One B-rep face of a CAD part: STEP entity #511.
In plain terms, the planar face has unit normal (1, 0, 0).
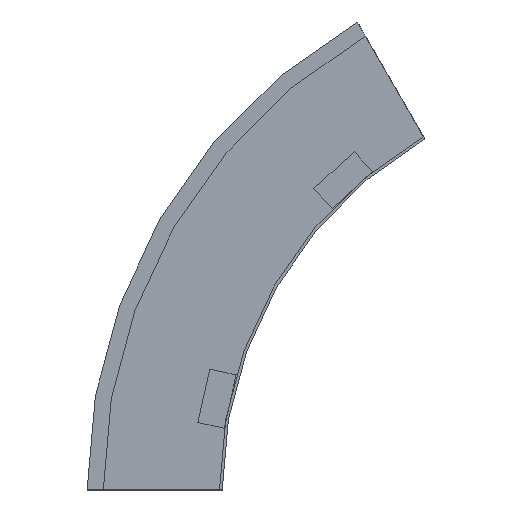
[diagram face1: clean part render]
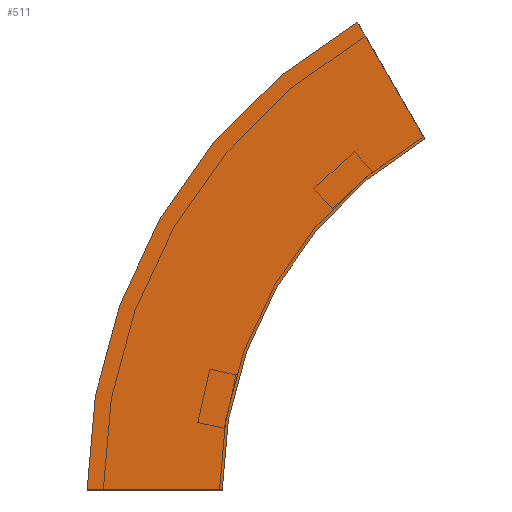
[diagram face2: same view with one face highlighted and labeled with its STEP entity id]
Its self-contained STEP definition (entity closure, numbers rounded to 3 decimals):
#20 = CARTESIAN_POINT ( 'NONE',  ( 0., -300., 0. ) ) ;
#27 = DIRECTION ( 'NONE',  ( 0., 0.5, 0.866 ) ) ;
#44 = VERTEX_POINT ( 'NONE', #328 ) ;
#50 = CARTESIAN_POINT ( 'NONE',  ( 0., 0., 0. ) ) ;
#91 = VERTEX_POINT ( 'NONE', #50 ) ;
#115 = AXIS2_PLACEMENT_3D ( 'NONE', #300, #396, #569 ) ;
#117 = LINE ( 'NONE', #428, #290 ) ;
#124 = CARTESIAN_POINT ( 'NONE',  ( 0., -100., 346.41 ) ) ;
#152 = VECTOR ( 'NONE', #256, 1000. ) ;
#178 = AXIS2_PLACEMENT_3D ( 'NONE', #20, #514, #205 ) ;
#181 = FACE_OUTER_BOUND ( 'NONE', #447, .T. ) ;
#191 = EDGE_CURVE ( 'NONE', #91, #44, #418, .T. ) ;
#205 = DIRECTION ( 'NONE',  ( 0., 1., 0. ) ) ;
#210 = VERTEX_POINT ( 'NONE', #124 ) ;
#256 = DIRECTION ( 'NONE',  ( 0., 1., 0. ) ) ;
#290 = VECTOR ( 'NONE', #27, 1000. ) ;
#300 = CARTESIAN_POINT ( 'NONE',  ( 0., 0., 0. ) ) ;
#308 = CARTESIAN_POINT ( 'NONE',  ( 0., -150., 259.808 ) ) ;
#328 = CARTESIAN_POINT ( 'NONE',  ( 0., 100., 0. ) ) ;
#336 = CARTESIAN_POINT ( 'NONE',  ( 0., -300., 0. ) ) ;
#356 = ORIENTED_EDGE ( 'NONE', *, *, #470, .F. ) ;
#372 = CIRCLE ( 'NONE', #178, 400. ) ;
#381 = CARTESIAN_POINT ( 'NONE',  ( 0., 0., 0. ) ) ;
#396 = DIRECTION ( 'NONE',  ( 1., 0., 0. ) ) ;
#397 = ORIENTED_EDGE ( 'NONE', *, *, #191, .T. ) ;
#418 = LINE ( 'NONE', #381, #152 ) ;
#428 = CARTESIAN_POINT ( 'NONE',  ( 0., -150., 259.808 ) ) ;
#429 = EDGE_CURVE ( 'NONE', #44, #210, #372, .T. ) ;
#434 = DIRECTION ( 'NONE',  ( 0., 1., 0. ) ) ;
#438 = ORIENTED_EDGE ( 'NONE', *, *, #429, .T. ) ;
#439 = PLANE ( 'NONE',  #115 ) ;
#447 = EDGE_LOOP ( 'NONE', ( #438, #356, #518, #397 ) ) ;
#449 = EDGE_CURVE ( 'NONE', #91, #525, #499, .T. ) ;
#470 = EDGE_CURVE ( 'NONE', #525, #210, #117, .T. ) ;
#471 = DIRECTION ( 'NONE',  ( 1., 0., 0. ) ) ;
#499 = CIRCLE ( 'NONE', #570, 300. ) ;
#511 = ADVANCED_FACE ( 'NONE', ( #181 ), #439, .T. ) ;
#514 = DIRECTION ( 'NONE',  ( 1., 0., 0. ) ) ;
#518 = ORIENTED_EDGE ( 'NONE', *, *, #449, .F. ) ;
#525 = VERTEX_POINT ( 'NONE', #308 ) ;
#569 = DIRECTION ( 'NONE',  ( 0., 0., -1. ) ) ;
#570 = AXIS2_PLACEMENT_3D ( 'NONE', #336, #471, #434 ) ;
